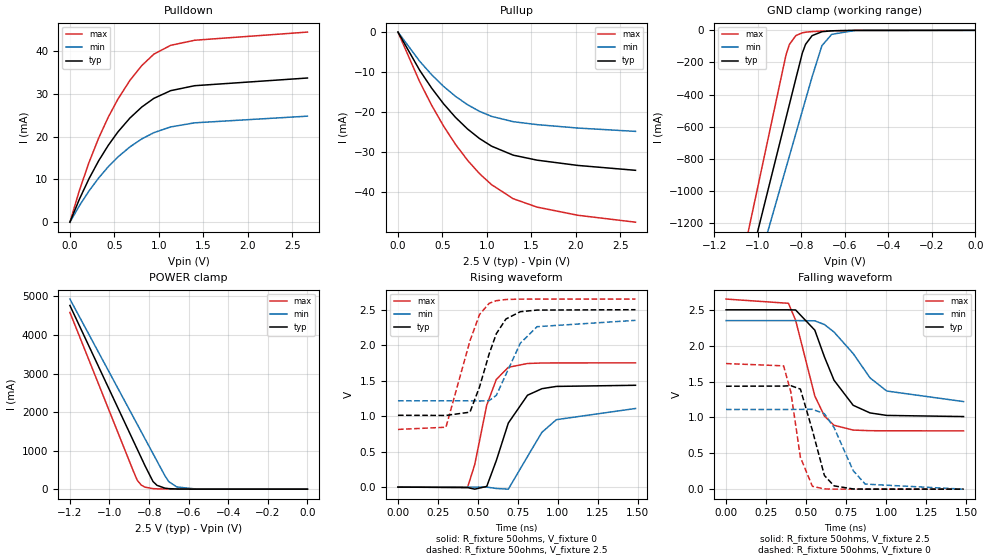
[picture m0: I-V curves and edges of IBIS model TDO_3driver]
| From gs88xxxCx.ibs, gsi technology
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|  signals   TDO
[Model]   TDO_3driver
Model_type   3-state
Polarity   Non-Inverting
Vmeas =   1.4v
Cref  =   0.0pF
Rref  =   50
Vref  =   1.4v
|  variable   typ   min   max
C_comp   3.0pF   2.5pF   3.5pF
|  variable   typ   min   max
[Temperature Range]   50   0   100
|  variable   typ   min   max
[Voltage Range]   2.5   2.35   2.65
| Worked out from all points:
|   slope of the pulldown table from 0 to 0.375 V, typ, clamps not added: 23.2 ohm
|   slope of the pullup table from 0 to 0.375 V, typ, clamps not added: 27 ohm
|   GND clamp passes 1 mA (typ) near -0.61 V on its own axis
|   POWER clamp passes 1 mA (typ) near -0.59 V on its own axis
|   rising waveform, R_fixture 50ohms, V_fixture 0: 20-80 % time 144ps typ, 184ps min, 107ps max; typ from 0 V to 1.44 V
|   rising waveform, R_fixture 50ohms, V_fixture 2.5: 20-80 % time 127ps typ, 147ps min, 132ps max; typ from 1.01 V to 2.5 V
|   falling waveform, R_fixture 50ohms, V_fixture 2.5: 20-80 % time 175ps typ, 241ps min, 133ps max; typ from 2.5 V to 1.01 V
|   falling waveform, R_fixture 50ohms, V_fixture 0: 20-80 % time 93ps typ, 136ps min, 72.9ps max; typ from 1.44 V to 0 V
[Pulldown]
| voltage   typ   min   max
0V        -354.4pA   -1.034nA   -211.5pA
108mV     5.444mA    3.903mA    7.511mA
216mV     10.22mA    7.345mA    14.05mA
324mV     14.39mA    10.36mA    19.71mA
432mV     18mA       12.99mA    24.6mA
540mV     21.12mA    15.26mA    28.8mA
675mV     24.37mA    17.62mA    33.18mA
810mV     26.98mA    19.51mA    36.68mA
945mV     28.99mA    20.96mA    39.34mA
1.134V    30.79mA    22.3mA     41.4mA
1.404V    31.95mA    23.26mA    42.59mA
2.673V    33.75mA    24.82mA    44.5mA
[Pullup]
| voltage (VDDQ-Vout)   typ   min   max
0V        284.9pA    1.042nA    119pA
243mV     -9.504mA   -7.26mA    -12.37mA
378mV     -14mA      -10.65mA   -18.28mA
513mV     -17.95mA   -13.59mA   -23.53mA
648mV     -21.37mA   -16.1mA    -28.13mA
783mV     -24.27mA   -18.18mA   -32.1mA
918mV     -26.66mA   -19.85mA   -35.45mA
1.053V    -28.56mA   -21.1mA    -38.2mA
1.296V    -30.81mA   -22.43mA   -41.71mA
1.566V    -32.07mA   -23.17mA   -43.83mA
2.025V    -33.39mA   -24.03mA   -45.87mA
2.673V    -34.61mA   -24.86mA   -47.6mA
[GND Clamp]
| voltage   typ   min   max
-1.485V   -3.884A    -3.771A    -4.056A
-885mV    -626.9mA   -926.9mA   -247.2mA
-870mV    -545.6mA   -856mA     -153.5mA
-855mV    -464.4mA   -785mA     -89.11mA
-825mV    -301.9mA   -643.2mA   -32.88mA
-795mV    -141.5mA   -501.4mA   -15.38mA
-780mV    -86.61mA   -430.5mA   -11.65mA
-750mV    -32.85mA   -288.8mA   -7.734mA
-705mV    -8.727mA   -95.28mA   -4.834mA
-660mV    -2.907mA   -24.97mA   -2.925mA
-555mV    -316.7uA   -1.176mA   -484.9uA
0V        -354.4pA   -1.034nA   -211.5pA
[POWER Clamp]
| voltage (VDDQ-Vout)   typ   min   max
-1.2V     4.765A     4.931A     4.585A
-880mV    1.258A     1.875A     474.1mA
-860mV    1.039A     1.684A     234.3mA
-840mV    820.4mA    1.493A     107.4mA
-820mV    601.5mA    1.302A     50.64mA
-780mV    197.3mA    920.5mA    14.28mA
-760mV    99.71mA    729.7mA    9.034mA
-720mV    26.23mA    348.2mA    4.898mA
-700mV    13.96mA    192.6mA    3.916mA
-660mV    4.495mA    57.55mA    2.579mA
-560mV    510.5uA    2.941mA    648.3uA
0V        285pA      1.042nA    119.1pA
[Ramp]
| voltage   typ   min   max
dV/dt_r   1.22/227p   0.98/347p   1.51/174p
dV/dt_f   1.15/220p   0.93/334p   1.40/169p
R_load  =   50ohms
[Rising Waveform]
C_fixture =   0.0pF
R_fixture =   50ohms
V_fixture =   0
| Time   V(typ)   V(min)   V(max)
0s        4.806nV    17.7nV     2.239nV
435ps     -6.875mV   506.6uV    -4.305mV
480ps     -28.91mV   711.5uV    318mV
555ps     9.634mV    -684.6uV   1.155V
615ps     374.9mV    -19.37mV   1.518V
690ps     903.2mV    -29.14mV   1.688V
810ps     1.295V     431.7mV    1.742V
900ps     1.387V     772.4mV    1.749V
990ps     1.419V     950.1mV    1.75V
1.485ns   1.435V     1.108V     1.751V
[Rising Waveform]
C_fixture =   0.0pF
R_fixture =   50ohms
V_fixture =   2.5
V_fixture_min =  2.35
V_fixture_max =  2.65
| Time   V(typ)   V(min)   V(max)
0s        1.012V     1.216V     812.7mV
300ps     1.01V      1.216V     843.9mV
450ps     1.056V     1.216V     2.061V
510ps     1.412V     1.213V     2.432V
570ps     1.877V     1.219V     2.59V
615ps     2.162V     1.293V     2.627V
675ps     2.369V     1.588V     2.644V
765ps     2.472V     2.028V     2.649V
870ps     2.495V     2.261V     2.65V
1.485ns   2.5V       2.35V      2.65V
[Falling Waveform]
C_fixture =   0.0pF
R_fixture =   50ohms
V_fixture =   2.5
V_fixture_min =  2.35
V_fixture_max =  2.65
| Time   V(typ)   V(min)   V(max)
0s        2.5V       2.35V      2.65V
390ps     2.5V       2.35V      2.591V
435ps     2.498V     2.35V      2.356V
555ps     2.217V     2.347V     1.299V
615ps     1.845V     2.295V     1.02V
675ps     1.519V     2.191V     890.9mV
795ps     1.169V     1.89V      823.7mV
900ps     1.063V     1.552V     815.1mV
1.005ns   1.028V     1.368V     813.5mV
1.485ns   1.012V     1.221V     813mV
[Falling Waveform]
C_fixture =   0.0pF
R_fixture =   50ohms
V_fixture =   0
| Time   V(typ)   V(min)   V(max)
0s        1.435V     1.111V     1.751V
360ps     1.437V     1.11V      1.719V
405ps     1.443V     1.111V     1.356V
465ps     1.395V     1.112V     443.4mV
540ps     820mV      1.113V     39.52mV
615ps     190.7mV    1.052V     3.231mV
675ps     46.11mV    860.4mV    543.4uV
795ps     2.9mV      257.8mV    38.32uV
870ps     596.6uV    70.66mV    9.691uV
1.485ns   1.862uV    9.427uV    728.4nV
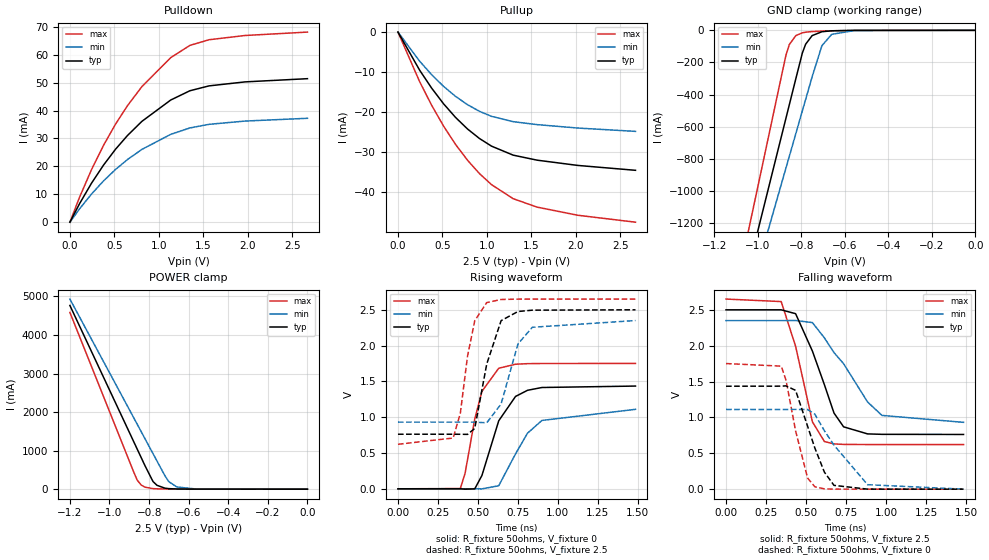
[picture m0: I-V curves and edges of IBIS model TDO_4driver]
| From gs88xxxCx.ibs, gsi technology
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|  signals   TDO
[Model]   TDO_4driver
Model_type   3-state
Polarity   Non-Inverting
Vmeas =   1.2v
Cref  =   0pF
Rref  =   50
Vref  =   1.2v
|  variable   typ   min   max
C_comp   3.0pF   2.5pF   3.5pF
|  variable   typ   min   max
[Temperature Range]   50   0   100
|  variable   typ   min   max
[Voltage Range]   2.5   2.35   2.65
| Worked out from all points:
|   slope of the pulldown table from 0 to 0.375 V, typ, clamps not added: 18.5 ohm
|   slope of the pullup table from 0 to 0.375 V, typ, clamps not added: 27 ohm
|   GND clamp passes 1 mA (typ) near -0.61 V on its own axis
|   POWER clamp passes 1 mA (typ) near -0.59 V on its own axis
|   rising waveform, R_fixture 50ohms, V_fixture 0: 20-80 % time 139ps typ, 178ps min, 102ps max; typ from 0 V to 1.44 V
|   rising waveform, R_fixture 50ohms, V_fixture 2.5: 20-80 % time 91ps typ, 113ps min, 77.9ps max; typ from 0.763 V to 2.5 V
|   falling waveform, R_fixture 50ohms, V_fixture 2.5: 20-80 % time 170ps typ, 258ps min, 125ps max; typ from 2.5 V to 0.763 V
|   falling waveform, R_fixture 50ohms, V_fixture 0: 20-80 % time 132ps typ, 216ps min, 95.9ps max; typ from 1.44 V to 0 V
[Pulldown]
| voltage   I(typ)   I(min)   I(max)
0V        -364.2pA   -1.049nA   -219.7pA
108mV     6.602mA    4.763mA    8.908mA
243mV     13.97mA    10.09mA    18.82mA
378mV     20.45mA    14.78mA    27.52mA
513mV     26.13mA    18.89mA    35.13mA
648mV     31.07mA    22.46mA    41.77mA
810mV     36.14mA    26.09mA    48.59mA
1.134V    43.78mA    31.48mA    58.96mA
1.35V     47.11mA    33.78mA    63.37mA
1.566V    48.86mA    35.08mA    65.4mA
1.971V    50.29mA    36.25mA    66.92mA
2.673V    51.44mA    37.24mA    68.14mA
[Pullup]
| voltage (VDDQ-Vout)   I(typ)   I(min)   I(max)
0V        284.9pA    1.042nA    119pA
243mV     -9.504mA   -7.26mA    -12.37mA
378mV     -14mA      -10.65mA   -18.28mA
513mV     -17.95mA   -13.59mA   -23.53mA
648mV     -21.37mA   -16.1mA    -28.13mA
783mV     -24.27mA   -18.18mA   -32.1mA
918mV     -26.66mA   -19.85mA   -35.45mA
1.053V    -28.56mA   -21.1mA    -38.2mA
1.296V    -30.81mA   -22.43mA   -41.71mA
1.566V    -32.07mA   -23.17mA   -43.83mA
2.025V    -33.39mA   -24.03mA   -45.87mA
2.673V    -34.61mA   -24.86mA   -47.6mA
[GND Clamp]
| voltage   I(typ)   I(min)   I(max)
-1.485V   -3.884A    -3.771A    -4.056A
-885mV    -626.9mA   -926.9mA   -247.2mA
-870mV    -545.6mA   -856mA     -153.5mA
-855mV    -464.4mA   -785mA     -89.11mA
-825mV    -301.9mA   -643.2mA   -32.88mA
-795mV    -141.5mA   -501.4mA   -15.38mA
-780mV    -86.61mA   -430.5mA   -11.65mA
-750mV    -32.85mA   -288.8mA   -7.734mA
-705mV    -8.727mA   -95.28mA   -4.834mA
-660mV    -2.907mA   -24.97mA   -2.925mA
-555mV    -316.7uA   -1.176mA   -484.9uA
0V        -354.4pA   -1.034nA   -211.5pA
[POWER Clamp]
| voltage (VDDQ-Vout)   I(typ)   I(min)   I(max)
-1.2V     4.765A     4.931A     4.585A
-880mV    1.258A     1.875A     474.1mA
-860mV    1.039A     1.684A     234.3mA
-840mV    820.4mA    1.493A     107.4mA
-820mV    601.5mA    1.302A     50.64mA
-780mV    197.3mA    920.5mA    14.28mA
-760mV    99.71mA    729.7mA    9.034mA
-720mV    26.23mA    348.2mA    4.898mA
-700mV    13.96mA    192.6mA    3.916mA
-660mV    4.495mA    57.55mA    2.579mA
-560mV    510.5uA    2.941mA    648.3uA
0V        285pA      1.042nA    119.1pA
[Ramp]
| voltage   typ   min   max
dV/dt_r   0.42/177p   0.22/231p   0.68/140p
dV/dt_f   0.41/174p   0.28/292p   0.56/120p
R_load  =   50ohms
[Rising Waveform]
C_fixture =   0.0pF
R_fixture =   50ohms
V_fixture =   0
| Time   V(typ)   V(min)   V(max)
0s        4.324nV    15.83nV    2.057nV
390ps     300.6uV    336.9uV    3.926mV
420ps     -4.922mV   614.7uV    220.6mV
480ps     -880.9uV   799.1uV    973.5mV
525ps     186.7mV    -711.2uV   1.362V
630ps     950.5mV    42.86mV    1.684V
735ps     1.29V      488.1mV    1.74V
810ps     1.376V     776.9mV    1.748V
900ps     1.415V     954.8mV    1.75V
1.485ns   1.435V     1.11V      1.751V
[Rising Waveform]
C_fixture =   0.0pF
R_fixture =   50ohms
V_fixture =   2.5
V_fixture_min =  2.35
V_fixture_max =  2.65
| Time   V(typ)   V(min)   V(max)
0s        762.5mV    931mV      621.9mV
345ps     762.3mV    931mV      709.4mV
390ps     761.7mV    931.3mV    1.056V
435ps     760.3mV    931.7mV    1.854V
480ps     843.4mV    931mV      2.348V
555ps     1.743V     921.8mV    2.601V
645ps     2.349V     1.185V     2.644V
750ps     2.476V     2.023V     2.649V
840ps     2.495V     2.256V     2.65V
1.485ns   2.5V       2.35V      2.65V
[Falling Waveform]
C_fixture =   0.0pF
R_fixture =   50ohms
V_fixture =   2.5
V_fixture_min =  2.35
V_fixture_max =  2.65
| Time   V(typ)   V(min)   V(max)
0s        2.5V       2.35V      2.65V
345ps     2.5V       2.35V      2.615V
435ps     2.446V     2.351V     1.991V
540ps     1.925V     2.322V     938.8mV
615ps     1.456V     2.109V     664.4mV
675ps     1.061V     1.904V     630.7mV
735ps     869mV      1.749V     624mV
885ps     770.3mV    1.215V     622.1mV
975ps     764.4mV    1.028V     622mV
1.485ns   762.7mV    931.5mV    622mV
[Falling Waveform]
C_fixture =   0.0pF
R_fixture =   50ohms
V_fixture =   0
| Time   V(typ)   V(min)   V(max)
0s        1.435V     1.111V     1.751V
345ps     1.436V     1.111V     1.715V
375ps     1.44V      1.11V      1.519V
435ps     1.377V     1.112V     811.3mV
510ps     877mV      1.11V      154.9mV
555ps     575.7mV    1.046V     33.25mV
615ps     237.1mV    814.3mV    4.086mV
675ps     52.88mV    613.1mV    593.3uV
885ps     328.4uV    62.21mV    9.486uV
1.485ns   1.109uV    5.329uV    458.8nV
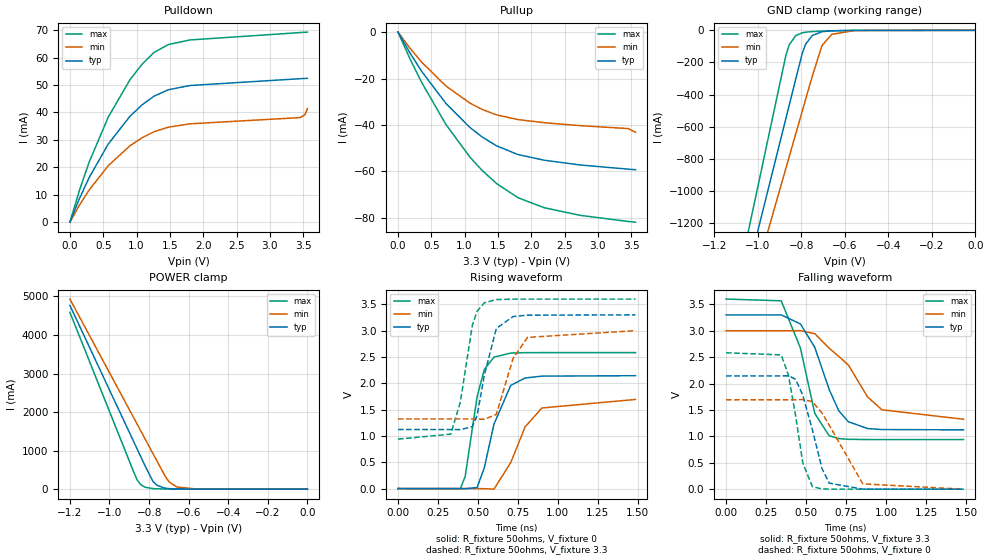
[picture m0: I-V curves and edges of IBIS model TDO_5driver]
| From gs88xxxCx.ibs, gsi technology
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|  signals   TDO
[Model]   TDO_5driver
Model_type   3-state
Polarity   Non-Inverting
Vmeas =   1.2v
Cref  =   0pF
Rref  =   50
Vref  =   1.2v
|  variable   typ   min   max
C_comp   3.0pF   2.5pF   3.5pF
|  variable   typ   min   max
[Temperature Range]   50   0   100
|  variable   typ   min   max
[Voltage Range]   3.3   3.0   3.6
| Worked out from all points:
|   slope of the pulldown table from 0 to 0.495 V, typ, clamps not added: 19.5 ohm
|   slope of the pullup table from 0 to 0.495 V, typ, clamps not added: 21.9 ohm
|   GND clamp passes 1 mA (typ) near -0.61 V on its own axis
|   POWER clamp passes 1 mA (typ) near -0.59 V on its own axis
|   rising waveform, R_fixture 50ohms, V_fixture 0: 20-80 % time 111ps typ, 148ps min, 82.3ps max; typ from 0 V to 2.14 V
|   rising waveform, R_fixture 50ohms, V_fixture 3.3: 20-80 % time 84.4ps typ, 103ps min, 84.7ps max; typ from 1.12 V to 3.3 V
|   falling waveform, R_fixture 50ohms, V_fixture 3.3: 20-80 % time 172ps typ, 264ps min, 127ps max; typ from 3.3 V to 1.12 V
|   falling waveform, R_fixture 50ohms, V_fixture 0: 20-80 % time 109ps typ, 178ps min, 82.4ps max; typ from 2.14 V to 0 V
[Pulldown]
| voltage   I(typ)   I(min)   I(max)
0V        -445.6pA   -1.181nA   -285.9pA
144mV     8.659mA    6.25mA     11.68mA
288mV     16.23mA    11.72mA    21.85mA
576mV     28.52mA    20.62mA    38.35mA
900mV     38.58mA    27.83mA    51.88mA
1.08V     42.72mA    30.74mA    57.51mA
1.26V     45.91mA    32.95mA    61.84mA
1.476V    48.28mA    34.64mA    64.76mA
1.8V      49.83mA    35.86mA    66.44mA
3.456V    52.32mA    38.14mA    69.14mA
3.528V    52.41mA    39.22mA    69.25mA
3.564V    52.46mA    41.4mA     69.31mA
[Pullup]
| voltage (VDDQ-Vout)   I(typ)   I(min)   I(max)
0V        394.9pA    1.311nA    168.6pA
180mV     -8.998mA   -6.92mA    -11.49mA
360mV     -17.1mA    -13.09mA   -21.93mA
720mV     -30.75mA   -23.23mA   -39.81mA
1.08V     -41.11mA   -30.6mA    -53.87mA
1.26V     -45.12mA   -33.28mA   -59.52mA
1.476V    -48.95mA   -35.65mA   -65.16mA
1.8V      -52.75mA   -37.68mA   -71.34mA
2.196V    -55.2mA    -39.04mA   -75.67mA
2.736V    -57.25mA   -40.31mA   -78.95mA
3.456V    -59.05mA   -41.57mA   -81.58mA
3.564V    -59.27mA   -43.17mA   -81.89mA
[GND Clamp]
| voltage   I(typ)   I(min)   I(max)
-1.485V   -3.884A    -3.771A    -4.056A
-885mV    -626.9mA   -926.9mA   -247.2mA
-870mV    -545.6mA   -856mA     -153.5mA
-855mV    -464.4mA   -785mA     -89.11mA
-825mV    -301.9mA   -643.2mA   -32.88mA
-795mV    -141.5mA   -501.4mA   -15.38mA
-780mV    -86.61mA   -430.5mA   -11.65mA
-750mV    -32.85mA   -288.8mA   -7.734mA
-705mV    -8.727mA   -95.28mA   -4.834mA
-660mV    -2.907mA   -24.97mA   -2.925mA
-555mV    -316.7uA   -1.176mA   -484.9uA
0V        -445.6pA   -1.181nA   -285.9pA
[POWER Clamp]
| voltage (VDDQ-Vout)   I(typ)   I(min)   I(max)
-1.2V     4.765A     4.931A     4.585A
-880mV    1.258A     1.875A     474.1mA
-860mV    1.039A     1.684A     234.3mA
-840mV    820.4mA    1.493A     107.4mA
-820mV    601.5mA    1.302A     50.64mA
-780mV    197.3mA    920.5mA    14.28mA
-760mV    99.71mA    729.7mA    9.034mA
-720mV    26.23mA    348.2mA    4.898mA
-700mV    13.96mA    192.6mA    3.916mA
-660mV    4.495mA    57.55mA    2.579mA
-560mV    510.5uA    2.941mA    648.3uA
0V        395pA      1.311nA    168.9pA
[Ramp]
| voltage   typ   min   max
dV/dt_r   0.42/174p   0.22/233p   0.68/137p
dV/dt_f   0.63/140p   0.48/233p   0.79/102p
R_load  =   50ohms
[Rising Waveform]
C_fixture =   0.0pF
R_fixture =   50ohms
V_fixture =   0
| Time   V(typ)   V(min)   V(max)
0s        5.291nV    17.82nV    2.677nV
390ps     65.54uV    312.3uV    -2.05mV
420ps     -4.733mV   544.3uV    230mV
495ps     20.83mV    393.9uV    1.748V
540ps     397.8mV    -2.623mV   2.264V
600ps     1.222V     -11.48mV   2.496V
705ps     1.96V      492.5mV    2.574V
795ps     2.101V     1.173V     2.582V
900ps     2.136V     1.531V     2.583V
1.485ns   2.144V     1.693V     2.583V
[Rising Waveform]
C_fixture =   0.0pF
R_fixture =   50ohms
V_fixture =   3.3
V_fixture_min =  3.0
V_fixture_max =  3.6
| Time   V(typ)   V(min)   V(max)
0s        1.122V     1.323V     939.2mV
330ps     1.121V     1.323V     1.034V
390ps     1.12V      1.323V     1.644V
465ps     1.175V     1.323V     3.102V
495ps     1.389V     1.321V     3.37V
540ps     2.153V     1.315V     3.529V
615ps     3.043V     1.41V      3.59V
720ps     3.268V     2.475V     3.599V
810ps     3.294V     2.872V     3.6V
1.485ns   3.3V       3V         3.6V
[Falling Waveform]
C_fixture =   0.0pF
R_fixture =   50ohms
V_fixture =   3.3
V_fixture_min =  3.0
V_fixture_max =  3.6
| Time   V(typ)   V(min)   V(max)
0s        3.3V       3V         3.6V
345ps     3.3V       3V         3.567V
465ps     3.129V     3.001V     2.673V
555ps     2.685V     2.945V     1.433V
645ps     1.885V     2.668V     1.011V
705ps     1.485V     2.514V     957.8mV
765ps     1.277V     2.35V      944.3mV
885ps     1.148V     1.746V     939.8mV
975ps     1.129V     1.503V     939.5mV
1.485ns   1.123V     1.324V     939.3mV
[Falling Waveform]
C_fixture =   0.0pF
R_fixture =   50ohms
V_fixture =   0
| Time   V(typ)   V(min)   V(max)
0s        2.144V     1.693V     2.583V
345ps     2.145V     1.693V     2.543V
390ps     2.148V     1.693V     2.163V
435ps     2.08V      1.694V     1.392V
480ps     1.78V      1.696V     494.3mV
540ps     1.121V     1.658V     47.73mV
600ps     391.1mV    1.443V     4.465mV
645ps     114.3mV    1.212V     836.3uV
855ps     412.3uV    100.3mV    10.3uV
1.485ns   1.082uV    4.087uV    454.6nV
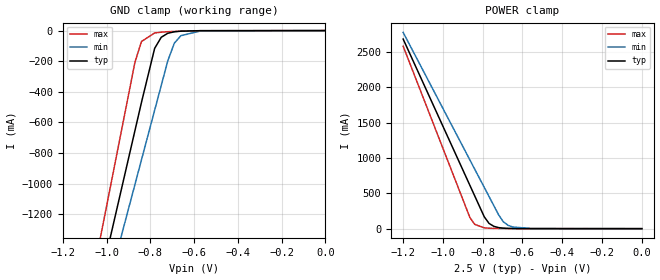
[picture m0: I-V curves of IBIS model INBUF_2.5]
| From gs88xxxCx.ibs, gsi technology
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| signals   A0-A18, CK, E1#, E@, E3#, BA#, BB#, BC#, BD#, W#,
|   ADV, G#, CKE#, ZZ
[Model]   INBUF_2.5
Model_type   Input
Vinl  =   0.75v
Vinh  =   1.75v
|  variable   typ   min   max
C_comp   3.0pF   2.5pF   3.5pF
|  variable   typ   min   max
[Temperature Range]   50   0   100
|  variable   typ   min   max
[Voltage Range]   2.5   2.375   2.7
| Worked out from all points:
|   GND clamp passes 1 mA (typ) near -0.59 V on its own axis
|   POWER clamp passes 1 mA (typ) near -0.62 V on its own axis
[GND Clamp]
| voltage   typ   min   max
-1.5V     -4.551A    -4.403A    -4.774A
-870mV    -652.3mA   -1.004A    -205.4mA
-840mV    -467.1mA   -842.2mA   -70.84mA
-780mV    -115.9mA   -519.6mA   -15.58mA
-750mV    -43.87mA   -358.5mA   -10.33mA
-720mV    -17.67mA   -197.5mA   -7.517mA
-690mV    -7.854mA   -81.59mA   -5.512mA
-660mV    -3.862mA   -33.3mA    -3.899mA
-570mV    -580.9uA   -2.381mA   -889.4uA
0V        -197.9pA   -579.6pA   -117.6pA
[POWER Clamp]
| voltage (VDDQ-Vout)   typ   min   max
-1.2V     2.682A     2.776A     2.581A
-864mV    609.9mA    969.4mA    154.4mA
-840mV    462mA      840.5mA    60.63mA
-792mV    167mA      582.7mA    11.33mA
-768mV    73.93mA    453.8mA    6.075mA
-744mV    32.79mA    325mA      3.861mA
-720mV    14.87mA    196.2mA    2.777mA
-696mV    7.029mA    96.32mA    2.126mA
-672mV    3.522mA    46.74mA    1.657mA
-648mV    1.888mA    22.66mA    1.278mA
-552mV    244.7uA    1.326mA    315.6uA
0V        357.2pA    1.359nA    137.2pA
